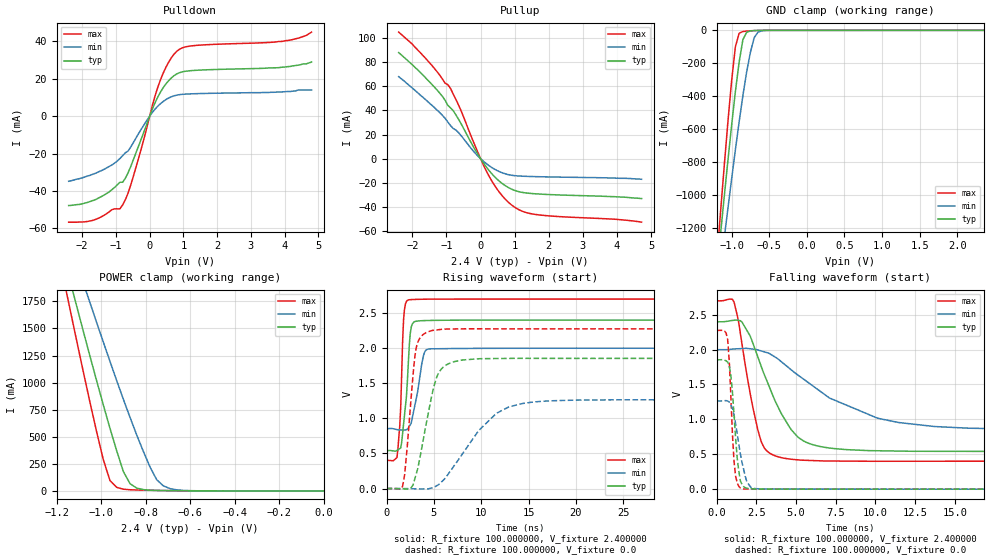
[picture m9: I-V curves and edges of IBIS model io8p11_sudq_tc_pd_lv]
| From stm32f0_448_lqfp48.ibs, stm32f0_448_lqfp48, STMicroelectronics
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|   Model io8p11_sudq_tc_pd_lv
[Model]  io8p11_sudq_tc_pd_lv
Model_type I/O
Polarity   Non-Inverting
Enable   Active-Low
Vinl =   0.720000V
Vinh =   1.680000V
Vmeas =  1.200000V
Cref =   50.000000pF
Rref =   100.000000M
Vref =   0.0V
C_comp   1.378000pF   1.292700pF   1.486400pF
[Temperature Range]   25.000000   0.125000k   -40.000000
[Pullup Reference]   2.400000V   2.000000V   2.700000V
[Pulldown Reference]   0.0V   0.0V   0.0V
[POWER Clamp Reference]   2.400000V   2.000000V   2.700000V
[GND Clamp Reference]   0.0V   0.0V   0.0V
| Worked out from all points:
|   slope of the pulldown table from 0 to 0.36 V, typ, clamps not added: 25.7 ohm
|   slope of the pullup table from 0 to 0.36 V, typ, clamps not added: 26.8 ohm
|   GND clamp passes 1 mA (typ) near -0.67 V on its own axis
|   POWER clamp passes 1 mA (typ) near -0.60 V on its own axis
|   rising waveform, R_fixture 100.000000, V_fixture 2.400000: 20-80 % time 603ps typ, 881ps min, 369ps max; typ from 0.541 V to 2.4 V
|   rising waveform, R_fixture 100.000000, V_fixture 0.0: 20-80 % time 1.64ns typ, 4.38ns min, 858ps max; typ from 0 V to 1.85 V
|   falling waveform, R_fixture 100.000000, V_fixture 2.400000: 20-80 % time 2.14ns typ, 5.07ns min, 1.09ns max; typ from 2.4 V to 0.541 V
|   falling waveform, R_fixture 100.000000, V_fixture 0.0: 20-80 % time 378ps typ, 596ps min, 283ps max; typ from 1.85 V to 0 V
[Pulldown]
|Voltage   I(typ)   I(min)   I(max)
-2.4V     -47.8mA    -34.8mA    -56.7mA
-1.68V    -45.1mA    -31mA      -55.7mA
-1.12V    -39.3mA    -26.1mA    -50.03mA
-800mV    -35.33mA   -21.13mA   -47.42mA
-640mV    -30.33mA   -18.65mA   -41.16mA
-480mV    -23.12mA   -14mA      -31.94mA
240mV     10.22mA    5.339mA    15.38mA
480mV     17.22mA    8.864mA    26.1mA
800mV     22.59mA    11.27mA    34.68mA
1.36V     24.54mA    12.05mA    37.84mA
3.92V     26.2mA     13mA       40mA
4.8V      29mA       14mA       45mA
[Pullup]
|Voltage   I(typ)   I(min)   I(max)
-2.4V     88mA       68mA       105mA
-2V       77.9mA     58.6mA     95mA
-1.36V    59.6mA     42.6mA     75.1mA
-880mV    42.13mA    27.44mA    58.22mA
-560mV    28.45mA    18.75mA    39mA
-160mV    7.44mA     4.66mA     10.64mA
160mV     -6.607mA   -3.947mA   -9.704mA
480mV     -16.91mA   -9.806mA   -25.1mA
880mV     -24.89mA   -13.63mA   -37.75mA
1.2V      -27.87mA   -14.5mA    -43.37mA
1.6V      -29.13mA   -14.89mA   -46.24mA
4.72V     -33.1mA    -17.1mA    -52.7mA
[GND_clamp]
|Voltage   I(typ)   I(min)   I(max)
-2.4V     -7.358A    -6.372A    -8.78A
-1.2V     -1.489A    -1.65A     -1.416A
-1.15V    -1.254A    -1.461A    -1.124A
-1.1V     -1.024A    -1.273A    -838.2mA
-1.05V    -797.6mA   -1.088A    -563.2mA
-950mV    -374.6mA   -728.7mA   -100.8mA
-900mV    -194.3mA   -558mA     -18.03mA
-850mV    -56.96mA   -397.5mA   -7.097mA
-750mV    -3.597mA   -133.8mA   -2.788mA
-700mV    -1.53mA    -44.71mA   -1.533mA
-600mV    -249.2uA   -2.951mA   -225.1uA
2.35V     60.02uA    46.69uA    67.1uA
[POWER_clamp]
|Voltage   I(typ)   I(min)   I(max)
-2.4V     9.979A     9.967A     9.901A
-1.17V    2.182A     2.481A     1.978A
-1.14V    1.945A     2.294A     1.683A
-1.11V    1.71A      2.108A     1.391A
-1.08V    1.476A     1.923A     1.102A
-1.05V    1.245A     1.739A     819.9mA
-960mV    578.2mA    1.196A     96.06mA
-900mV    179.5mA    846.7mA    16.04mA
-870mV    67.18mA    678.8mA    10.82mA
-780mV    6.749mA    219.9mA    5.853mA
-720mV    3.355mA    46.34mA    3.808mA
0V        0A         0A         0A
[Ramp]
| variable   typ   min   max
dV/dt_r  1.11234/1.64079n   0.75852/4.37975n   1.36500/0.85446n
dV/dt_f  1.11470/2.13842n   0.68714/5.06100n   1.37918/1.09189n
R_load = 100.000000
[Rising Waveform]
R_fixture= 100.000000
V_fixture= 2.400000
V_fixture_min= 2.000000
V_fixture_max= 2.700000
|time   V(typ)   V(min)   V(max)
0s        541.2mV    853.5mV    400.3mV
1.101ns   543mV      839.8mV    441.9mV
1.502ns   578.2mV    834.9mV    1.17V
1.802ns   919.8mV    834.8mV    2.409V
2.302ns   1.788V     863.8mV    2.686V
2.503ns   2.203V     906.7mV    2.69V
2.703ns   2.339V     994.7mV    2.692V
3.904ns   2.392V     1.892V     2.697V
4.404ns   2.394V     1.986V     2.698V
49.85ns   2.399V     1.999V     2.699V
[Rising Waveform]
R_fixture= 100.000000
V_fixture= 0.0
V_fixture_min= 0.0
V_fixture_max= 0.0
|time   V(typ)   V(min)   V(max)
0s        765pV      13.32nV    588.1pV
1.702ns   -3.053mV   -57.82uV   36.22mV
2.002ns   -5.705mV   -163.8uV   325.4mV
3.103ns   192mV      -3.613mV   1.98V
4.404ns   1.069V     -4.713mV   2.233V
5.305ns   1.586V     40.34mV    2.26V
6.306ns   1.76V      167.1mV    2.272V
11.51ns   1.852V     1.06V      2.275V
14.31ns   1.855V     1.21V      2.275V
49.85ns   1.854V     1.264V     2.275V
[Falling Waveform]
R_fixture= 100.000000
V_fixture= 2.400000
V_fixture_min= 2.000000
V_fixture_max= 2.700000
|time   V(typ)   V(min)   V(max)
0s        2.399V     1.999V     2.699V
1.101ns   2.42V      2.009V     2.683V
1.602ns   2.394V     2.015V     2.08V
2.202ns   2.145V     2.009V     1.271V
2.803ns   1.765V     1.981V     688.4mV
4.204ns   1.035V     1.803V     445.6mV
6.406ns   616.9mV    1.422V     407mV
10.11ns   550.4mV    1.019V     399.9mV
13.71ns   542.4mV    897.7mV    400.2mV
49.85ns   541.2mV    853.5mV    400.3mV
[Falling Waveform]
R_fixture= 100.000000
V_fixture= 0.0
V_fixture_min= 0.0
V_fixture_max= 0.0
|time   V(typ)   V(min)   V(max)
0s        1.854V     1.264V     2.275V
700.7ps   1.822V     1.263V     2.142V
800.8ps   1.768V     1.249V     1.836V
900.9ps   1.633V     1.207V     1.341V
1.101ns   1.068V     1.062V     402.6mV
1.301ns   446.3mV    794.4mV    89.58mV
1.602ns   67.13mV    385.4mV    7.102mV
2.102ns   7.1mV      42.69mV    1.508mV
2.803ns   1.747mV    4.003mV    817.4uV
49.85ns   765pV      13.32nV    588.1pV
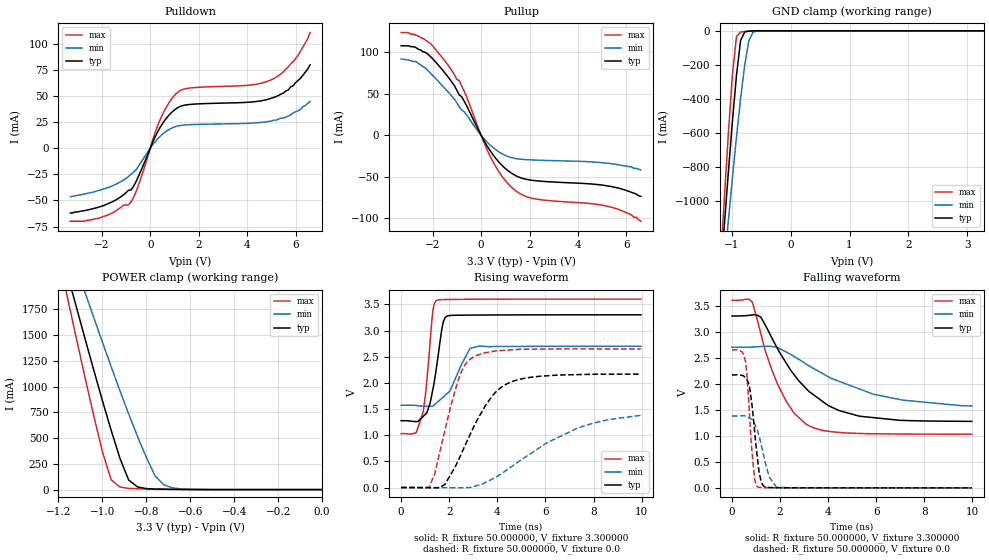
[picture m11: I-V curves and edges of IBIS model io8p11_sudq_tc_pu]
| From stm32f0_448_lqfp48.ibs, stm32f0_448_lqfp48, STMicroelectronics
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|   Model io8p11_sudq_tc_pu
[Model]  io8p11_sudq_tc_pu
Model_type I/O
Polarity   Non-Inverting
Enable   Active-Low
Vinl =   0.990000V
Vinh =   2.310000V
Vmeas =  1.650000V
Cref =   30.000000pF
Rref =   100.000000M
Vref =   0.0V
C_comp   1.329900pF   1.255600pF   1.431200pF
[Temperature Range]   25.000000   0.125000k   -40.000000
[Pullup Reference]   3.300000V   2.700000V   3.600000V
[Pulldown Reference]   0.0V   0.0V   0.0V
[POWER Clamp Reference]   3.300000V   2.700000V   3.600000V
[GND Clamp Reference]   0.0V   0.0V   0.0V
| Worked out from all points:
|   slope of the pulldown table from 0 to 0.495 V, typ, clamps not added: 21.3 ohm
|   slope of the pullup table from 0 to 0.495 V, typ, clamps not added: 20.9 ohm
|   GND clamp passes 1 mA (typ) near -0.67 V on its own axis
|   POWER clamp passes 1 mA (typ) near -0.60 V on its own axis
|   rising waveform, R_fixture 50.000000, V_fixture 3.300000: 20-80 % time 415ps typ, 733ps min, 311ps max; typ from 1.28 V to 3.3 V
|   rising waveform, R_fixture 50.000000, V_fixture 0.0: 20-80 % time 1.48ns typ, 2.98ns min, 896ps max; typ from 0.001 V to 2.17 V
|   falling waveform, R_fixture 50.000000, V_fixture 3.300000: 20-80 % time 2.06ns typ, 3.13ns min, 1.29ns max; typ from 3.3 V to 1.28 V
|   falling waveform, R_fixture 50.000000, V_fixture 0.0: 20-80 % time 303ps typ, 448ps min, 236ps max; typ from 2.17 V to 0.001 V
[Pulldown]
|Voltage   I(typ)   I(min)   I(max)
-3.3V     -62mA      -46.3mA    -70mA
-2.1V     -56.2mA    -40.3mA    -66.8mA
-800mV    -40.05mA   -24.9mA    -51.58mA
-500mV    -27.57mA   -17.6mA    -36.07mA
400mV     19.71mA    11.36mA    27.01mA
700mV     29.83mA    16.93mA    40.97mA
1.1V      38.46mA    21.2mA     53.02mA
1.6V      41.98mA    22.62mA    57.7mA
4.1V      44.26mA    24mA       60.59mA
5V        48mA       26.2mA     65.8mA
5.9V      60mA       34mA       83mA
6.6V      80mA       45mA       111mA
[Pullup]
|Voltage   I(typ)   I(min)   I(max)
-3.3V     108mA      92mA       124mA
-2.7V     106mA      89mA       121mA
-2.2V     98mA       78.1mA     113mA
-1.4V     71.8mA     53.5mA     86.1mA
-900mV    48.5mA     34.23mA    66.14mA
-700mV    41.33mA    28.36mA    53.31mA
400mV     -19.77mA   -12.52mA   -26.8mA
900mV     -37.48mA   -22.89mA   -50.99mA
1.4V      -48.39mA   -28.06mA   -66.43mA
2.2V      -54.79mA   -29.98mA   -76.75mA
5.3V      -61.6mA    -34.1mA    -86.4mA
6.6V      -74mA      -42mA      -104mA
[GND_clamp]
|Voltage   I(typ)   I(min)   I(max)
-3.3V     -9.739A    -9.975A    -9.587A
-1.2V     -1.489A    -1.65A     -1.416A
-1.13V    -1.162A    -1.385A    -1.009A
-1.06V    -842.2mA   -1.125A    -616.9mA
-990mV    -537.1mA   -870.1mA   -263mA
-920mV    -262.4mA   -625.3mA   -33.96mA
-850mV    -56.94mA   -397.4mA   -7.08mA
-780mV    -7.011mA   -202.2mA   -3.71mA
-710mV    -1.778mA   -58.23mA   -1.736mA
-640mV    -550uA     -8.783mA   -542.4uA
-570mV    -109.8uA   -1.292mA   -86.89uA
3.28V     0A         0A         0A
[POWER_clamp]
|Voltage   I(typ)   I(min)   I(max)
-3.28V    9.897A     9.838A     9.594A
-1.16V    2.103A     2.419A     1.88A
-1.12V    1.788A     2.17A      1.488A
-1.08V    1.476A     1.923A     1.102A
-1V       868.2mA    1.435A     373.1mA
-960mV    578.3mA    1.196A     96.08mA
-880mV    93.25mA    734.2mA    12.03mA
-840mV    26.31mA    517.4mA    8.576mA
-760mV    5.12mA     134mA      5.134mA
-720mV    3.368mA    46.35mA    3.823mA
-600mV    1.018mA    2.575mA    1.086mA
0V        0A         0A         0A
[Ramp]
| variable   typ   min   max
dV/dt_r  1.30001/1.47571n   0.78917/2.97302n   1.58846/0.89512n
dV/dt_f  1.21446/2.06713n   0.65838/3.12874n   1.54164/1.29260n
R_load = 50.000000
[Rising Waveform]
R_fixture= 50.000000
V_fixture= 3.300000
V_fixture_min= 2.700000
V_fixture_max= 3.600000
|time   V(typ)   V(min)   V(max)
0s        1.277V     1.572V     1.031V
620.6ps   1.261V     1.568V     1.045V
920.9ps   1.362V     1.554V     1.455V
1.081ns   1.443V     1.554V     2.117V
1.321ns   1.883V     1.554V     3.38V
1.502ns   2.398V     1.628V     3.58V
1.702ns   3.05V      1.71V      3.591V
1.822ns   3.242V     1.759V     3.592V
2.863ns   3.295V     2.658V     3.597V
9.97ns    3.3V       2.7V       3.6V
[Rising Waveform]
R_fixture= 50.000000
V_fixture= 0.0
V_fixture_min= 0.0
V_fixture_max= 0.0
|time   V(typ)   V(min)   V(max)
0s        951.9uV    1.086mV    928.7uV
1.161ns   -2.533mV   1.016mV    10.62mV
1.401ns   -4.814mV   543.2uV    275.2mV
1.822ns   62.41mV    -1.06mV    1.097V
2.362ns   508.1mV    -3.486mV   2.038V
3.003ns   1.147V     18.59mV    2.492V
3.824ns   1.769V     171mV      2.602V
4.745ns   2.045V     451.4mV    2.636V
7.307ns   2.158V     1.131V     2.65V
9.97ns    2.168V     1.379V     2.649V
[Falling Waveform]
R_fixture= 50.000000
V_fixture= 3.300000
V_fixture_min= 2.700000
V_fixture_max= 3.600000
|time   V(typ)   V(min)   V(max)
0s        3.3V       2.7V       3.6V
840.8ps   3.321V     2.704V     3.568V
1.201ns   3.276V     2.714V     2.957V
1.882ns   2.684V     2.697V     2.004V
2.583ns   2.173V     2.523V     1.435V
3.183ns   1.859V     2.349V     1.196V
4.024ns   1.575V     2.128V     1.086V
5.305ns   1.376V     1.898V     1.045V
7.107ns   1.296V     1.685V     1.033V
9.97ns    1.277V     1.572V     1.031V
[Falling Waveform]
R_fixture= 50.000000
V_fixture= 0.0
V_fixture_min= 0.0
V_fixture_max= 0.0
|time   V(typ)   V(min)   V(max)
0s        2.168V     1.379V     2.649V
400.4ps   2.161V     1.385V     2.617V
560.6ps   2.116V     1.377V     2.43V
740.7ps   1.904V     1.335V     1.323V
940.9ps   1.088V     1.227V     162.4mV
1.081ns   480.9mV    1.07V      18.3mV
1.301ns   41.19mV    653.6mV    4.78mV
1.542ns   8.693mV    221.4mV    3.169mV
1.862ns   3.97mV     8.264mV    2.479mV
9.97ns    951.9uV    1.086mV    928.7uV
